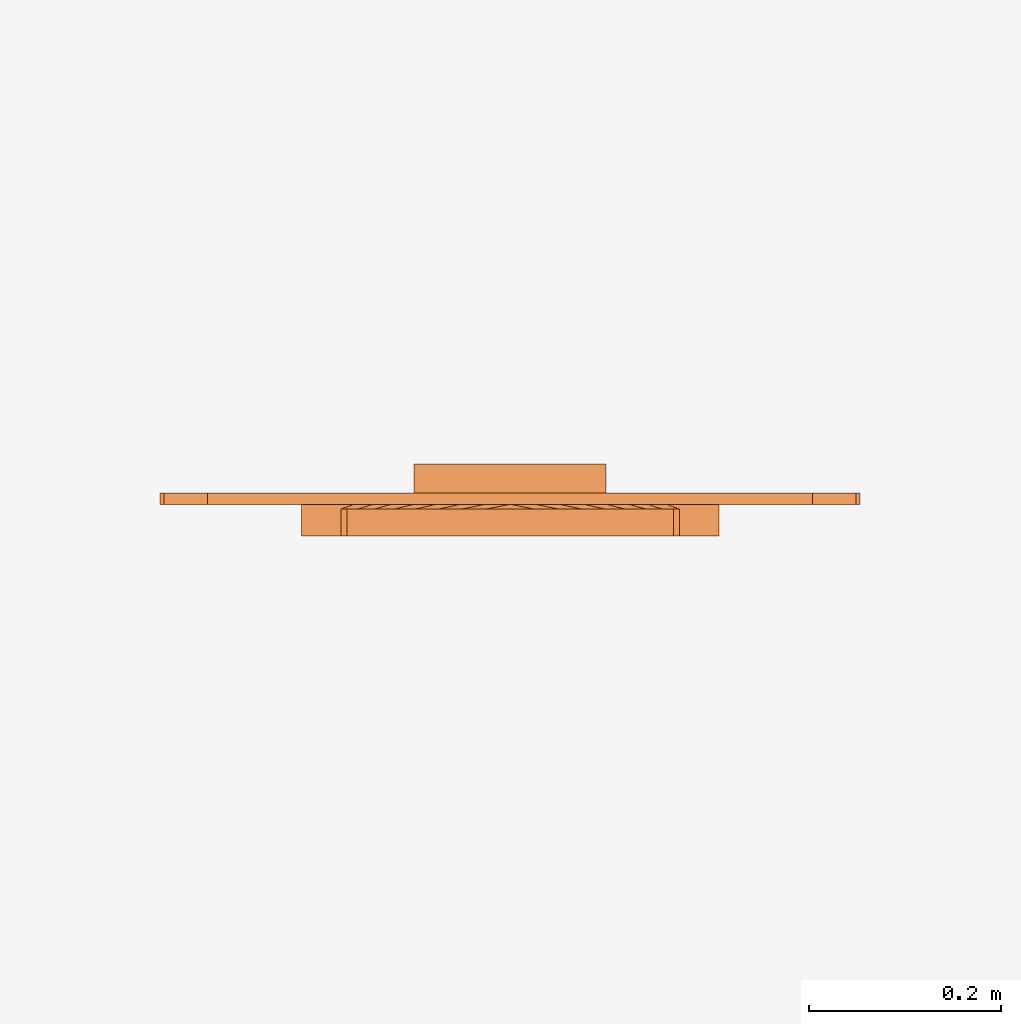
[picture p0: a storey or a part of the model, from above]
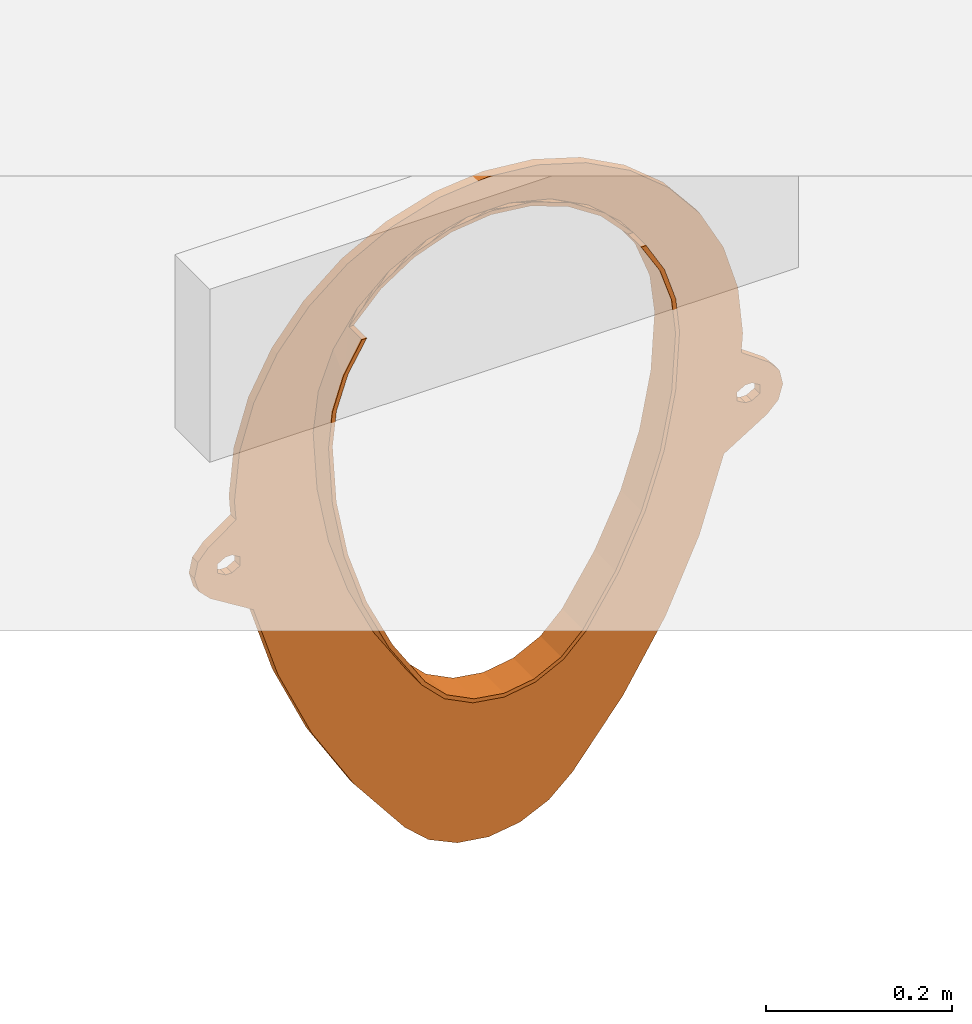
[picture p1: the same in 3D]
Properties of the parts of a building model (IFC2X3)

# File
Description: ViewDefinition [CoordinationView]
File name: 32882 - 550-700 Step Connector.ifc
Time: 2013-07-11T17:05:10
Written by: Autodesk Revit 2013
Made in: 20120221_2030(x64)

# IfcProject, Project Number
LongName: Project Name; Phase: Project Status

# IfcSite, Default
RefLatitude: 42, 21, 30, 344238; RefLongitude: -71, -3, -35, -194702; RefElevation: 0 mm

# IfcBuilding
Pset_BuildingCommon - NumberOfStoreys: 1
Other - Project Name: Project Name; Client Name: Owner; Project Number: Project Number; Project Issue Date: Issue Date; Project Address: ## Street City, State Zip; Project Status: Project Status

# IfcBuildingStorey, Level 1
LongName: Level 1; Elevation: 0 mm
Graphics - Line Weight: 1; Color: 0; Symbol at End 1 Default: no; Symbol: M_Level Head - Circle: M_Level Head - Circle; Line Pattern: Center; Symbol at End 2 Default: yes
Constraints - Elevation Base: 0; Elevation: 0 mm
Dimensions - Computation Height: 0 mm
Identity Data - Structural: no; Building Story: yes; Name: Level 1

# IfcBuildingElementProxy: 550-700 Step Connector, 550-700 Step Connector:550-700 Step Connector:550-700 Step Connector:503700
In: Level 1
Constraints - Level: Level: Level 1; Moves With Nearby Elements: no
Dimensions - Volume: 2825916 mm3; Step Connector_Depth: 580.3 mm
Phasing - Phase Created: New Construction
Pset_BuildingElementProxyCommon - Reference: 550-700 Step Connector

# IfcOpeningElement: Recess
In: Level 1
Phasing - Phase Created: New Construction
Dimensions - Volume: 54023600537 mm3; Thickness: 400 mm; Perimeter: 50000 mm; Area: 135090000 mm2
Constraints - Room Bounding: yes; Level: Level: Level 1; Related to Mass: no; Height Offset From Level: 0 mm
Structural - Enable Analytical Model: no; Structural: no
Analytical Properties - Roughness: 1; Absorptance: 0.1
Materials and Finishes - Structural Material: Plant
Graphics - Coarse Scale Fill Color: 0
Construction - Default Thickness: 400 mm; Function: 0

# IfcSlab: Floor:Generic Floor - 400mm, Floor:Generic Floor - 400mm:193825
In: Level 1
PredefinedType: FLOOR; Material: Plant 400 mm
Phasing - Phase Created: New Construction
Dimensions - Volume: 54023600537 mm3; Thickness: 400 mm; Perimeter: 50000 mm; Area: 135090000 mm2
Constraints - Room Bounding: yes; Level: Level: Level 1; Related to Mass: no; Height Offset From Level: 0 mm
Structural - Enable Analytical Model: no; Structural: no
Pset_SlabCommon - Reference: Generic Floor - 400mm; IsExternal: no; LoadBearing: yes
Analytical Properties - Roughness: 1; Absorptance: 0.1
Materials and Finishes - Structural Material: Plant
Graphics - Coarse Scale Fill Color: 0
Construction - Default Thickness: 400 mm; Function: 0
